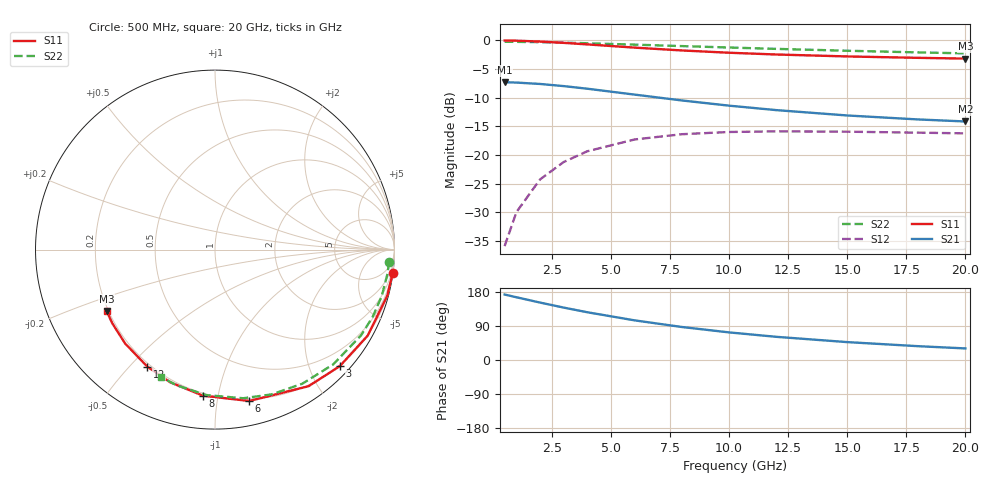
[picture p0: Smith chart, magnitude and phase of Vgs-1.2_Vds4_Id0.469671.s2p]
# Hz S RI R 50
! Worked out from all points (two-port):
!   12 points, 500 MHz to 20 GHz, reference 50 ohm
!   highest |S21| = -7.29 dB at 500 MHz (marker M1); lowest = -14.1 dB at 20 GHz (marker M2)
!   |S21| within 3 dB of the highest: start of sweep to 7.647 GHz
!   lowest |S11| = -3.2 dB at 20 GHz (marker M3), VSWR 5.53, Z = 9.64 - j12.7 ohm
!   |S11| at or under -10 dB: nowhere
!   |S22| runs from -2.3 to -0.2 dB; largest |S21 - S12| = 0.43
!   S11 on the Smith chart (normalised r, x): 500 MHz: 0, -15; 3 GHz: 0.18, -2.52; 6 GHz: 0.18, -1.24; 8 GHz: 0.18, -0.90; 12 GHz: 0.19, -0.56; 20 GHz: 0.19, -0.25
5e8  0.9899 -0.1304  -0.4284 0.0545  0.00152 0.016  0.97 -0.0665
1e9  0.9602 -0.2563  -0.4151 0.1069  0.00599 0.0312  0.9616 -0.1322
2e9  0.8505 -0.4796  -0.3665 0.1986  0.0223 0.0572  0.9291 -0.2586
3e9  0.6954 -0.6493  -0.2983 0.2657  0.0449 0.0745  0.8787 -0.3745
4e9  0.5211 -0.7612  -0.2228 0.3065  0.0693 0.0828  0.814 -0.4775
6e9  0.191 -0.8434  -0.085 0.3258  0.1119 0.0786  0.6582 -0.6398
8e9  -0.0663 -0.8141  0.0152 0.299  0.1396 0.0603  0.4864 -0.7472
1e10  -0.2494 -0.7393  0.0796 0.2576  0.154 0.0392  0.3162 -0.8066
1.2e10  -0.377 -0.6519  0.119 0.2159  0.1598 0.02  0.1575 -0.8282
1.5e10  -0.5001 -0.524  0.1504 0.1625  0.1599 -0.00258  -0.0489 -0.8106
1.8e10  -0.5728 -0.4098  0.1645 0.1215  0.1557 -0.0186  -0.2141 -0.7559
2e10  -0.6038 -0.3419  0.1691 0.0997  0.1523 -0.0266  -0.3033 -0.7081
